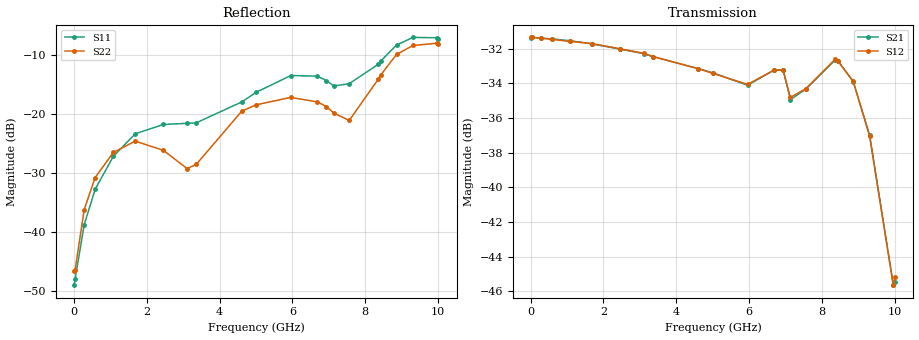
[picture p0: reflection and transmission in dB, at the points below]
! Device ID: PE43704
! Dir: z:\PE43704\PE43704_Char_1_20130516\PE43704\AMB\3p400V\30p50dB
! Serial: 14
! Insertion: A
! Impedance: 50 ohm
! Temp: Amb
! VDD: 3.400V
! Attenuation Step: 30.50dB
! IDD: 1.140609e-01mA
#  Hz  S  RI  R  50
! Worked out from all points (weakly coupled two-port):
!   401 points, 10 MHz to 10.01 GHz, reference 50 ohm
!   highest |S21| = -31.35 dB at 35 MHz (marker M1); lowest = -45.6 dB at 9.96 GHz (marker M2)
!   lowest |S11| = -49.0 dB at 10 MHz (marker M3), VSWR 1.01, Z = 50.4 + j0.0355 ohm
!   |S11| at or under -10 dB: start of sweep to 8.568 GHz
!   |S22| runs from -46.6 to -7.9 dB; largest |S21 - S12| = 0.00055
!   S11 on the Smith chart (normalised r, x): 10 MHz: 1.01, +0.00; 4.61 GHz: 0.79, +0.08; 8.435 GHz: 0.76, +0.46; 9.31 GHz: 0.51, +0.52; 10.01 GHz: 0.44, +0.31
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1e7  0.00351 0.000353  0.027 -9.54e-05  0.0271 -8.8e-05  -0.00466 0.000496
3.5e7  0.00366 0.00156  0.0271 -0.00023  0.0271 -0.000234  -0.00437 0.00186
2.85e8  0.000598 0.0115  0.0269 -0.00179  0.0269 -0.00179  -0.00656 0.014
5.85e8  -0.00982 0.0208  0.0266 -0.00356  0.0265 -0.00362  -0.0152 0.0246
1.085e9  -0.0373 0.0229  0.0257 -0.00649  0.0256 -0.00638  -0.0377 0.0285
1.685e9  -0.0677 0.00664  0.0241 -0.00963  0.0242 -0.00955  -0.0573 0.0139
2.46e9  -0.08 -0.0166  0.0215 -0.0129  0.0215 -0.013  -0.0492 -0.000661
3.11e9  -0.0817 -0.0169  0.0189 -0.0153  0.0189 -0.0154  -0.0333 0.00883
3.36e9  -0.0836 -0.0107  0.0177 -0.016  0.0177 -0.016  -0.0333 0.017
4.61e9  -0.1166 0.0499  0.0128 -0.0179  0.0128 -0.0179  -0.0864 0.0612
5.01e9  -0.1359 0.0713  0.0119 -0.0178  0.0119 -0.0177  -0.1057 0.0569
5.96e9  -0.1863 0.1026  0.00825 -0.0179  0.00853 -0.0179  -0.1314 0.0441
6.685e9  -0.1867 0.0961  0.00744 -0.0205  0.00743 -0.0205  -0.1219 0.0351
6.935e9  -0.1694 0.0914  0.00432 -0.0214  0.00417 -0.0214  -0.1088 0.0397
7.135e9  -0.1542 0.0794  0.00385 -0.0175  0.00375 -0.0178  -0.0915 0.0455
7.56e9  -0.1296 0.1265  0.00443 -0.0187  0.00428 -0.0188  -0.059 0.0657
8.36e9  -0.0594 0.2587  -0.00299 -0.0231  -0.00308 -0.0232  -0.0721 0.1847
8.435e9  -0.0606 0.2779  -0.0044 -0.0228  -0.0043 -0.0228  -0.0817 0.2008
8.86e9  -0.1008 0.3724  -0.0101 -0.0175  -0.00997 -0.0176  -0.1442 0.2869
9.31e9  -0.1827 0.4093  -0.00989 -0.0101  -0.00998 -0.0099  -0.2353 0.3016
9.96e9  -0.3214 0.3073  -0.00147 -0.00502  -0.00158 -0.00498  -0.3678 0.1559
1.001e10  -0.329 0.2883  -0.000574 -0.00532  -0.000875 -0.00545  -0.3724 0.1358
